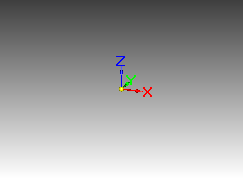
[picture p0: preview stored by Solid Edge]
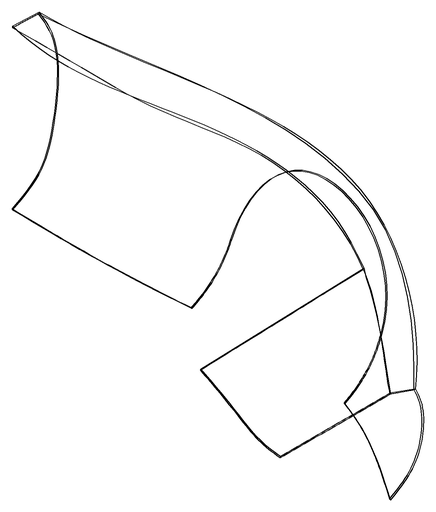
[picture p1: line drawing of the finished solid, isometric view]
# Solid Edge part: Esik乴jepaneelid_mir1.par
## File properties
Author: Türk
Template: Iso Part.par
Last saved by: Türk
Revision: 2
Application: Solid Edge
Accuracy: 0,990
Username: Türk
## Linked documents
ljepaneelid.par
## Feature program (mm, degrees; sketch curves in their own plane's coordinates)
part copy "CopiedPart_1"
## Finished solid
Body 1: solid body, 21 faces, 51 edges, 32 vertices.
  Faces by surface: spline 15, offset 3, plane 2, cylinder 1
  Edges by curve: intersection 21, curve on surface 19, spline 6, line 5
Bounding box of the edges (mm; curved faces can reach further): 899.653 x 1660.174 x 622.125, from (-899.6441, -960.1735, -150) to (0.009, 700, 472.1255).
Cylindrical faces by radius (mm): R300 x1
Planar faces by outward normal: +y 1, -y 1
